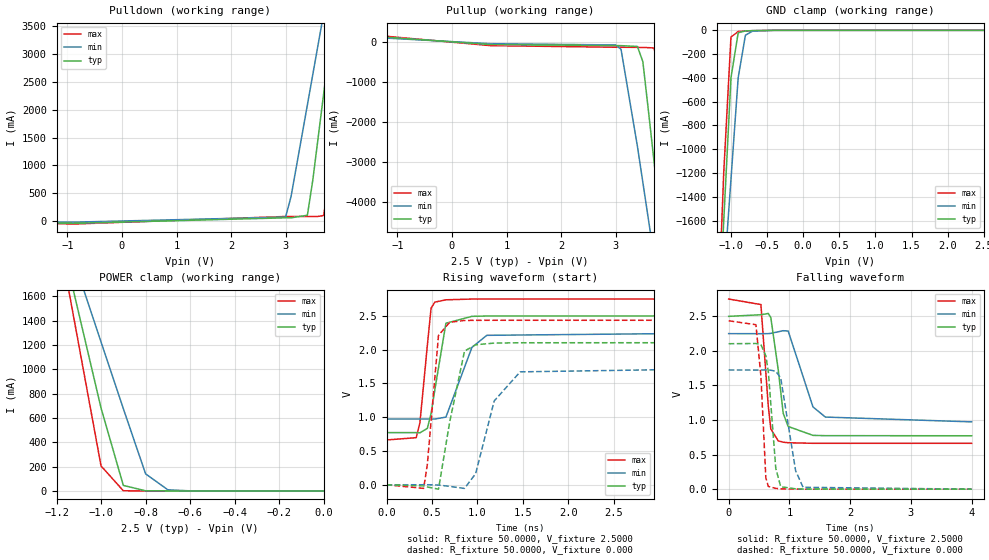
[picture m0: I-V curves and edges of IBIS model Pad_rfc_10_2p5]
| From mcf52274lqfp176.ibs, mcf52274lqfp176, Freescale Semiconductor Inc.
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|   Model Pad_rfc_10_2p5
[Model]   Pad_rfc_10_2p5
Model_type   3-state
Polarity   Non-Inverting
Enable   Active-High
Vmeas =   1.2500V
C_comp   1.7450pF   1.6200pF   1.8900pF
[Temperature Range]   25.0000   0.1500k   -40.0000
[Voltage Range]   2.5000V   2.2500V   2.7500V
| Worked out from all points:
|   slope of the pulldown table from 0 to 0.375 V, typ, clamps not added: 19.7 ohm
|   slope of the pullup table from 0 to 0.375 V, typ, clamps not added: 9.34 ohm
|   GND clamp passes 1 mA (typ) near -0.62 V on its own axis
|   POWER clamp passes 1 mA (typ) near -0.80 V on its own axis
|   rising waveform, R_fixture 50.0000, V_fixture 2.5000: 20-80 % time 119ps typ, 169ps min, 88.2ps max; typ from 0.772 V to 2.5 V
|   rising waveform, R_fixture 50.0000, V_fixture 0.000: 20-80 % time 141ps typ, 226ps min, 92.3ps max; typ from 0 V to 2.1 V
|   falling waveform, R_fixture 50.0000, V_fixture 2.5000: 20-80 % time 134ps typ, 249ps min, 97.3ps max; typ from 2.5 V to 0.772 V
|   falling waveform, R_fixture 50.0000, V_fixture 0.000: 20-80 % time 109ps typ, 183ps min, 83.4ps max; typ from 2.1 V to 0 V
[Pulldown]
| voltage   I(typ)   I(min)   I(max)
-2.5V     -1.24mA    -830uA     -1.5mA
-900mV    -41mA      -20.4mA    -54.37mA
3V        57.72mA    70.72mA    81.74mA
3.1V      57.87mA    437.7mA    81.94mA
3.4V      103.7mA    2.085A     82.48mA
3.5V      739.4mA    2.636A     82.66mA
3.6V      1.518A     3.187A     82.95mA
3.7V      2.298A     3.738A     100.1mA
3.8V      3.078A     4.29A      786mA
4V        4.642A     5.395A     2.779A
4.2V      6.207A     6.501A     4.776A
5V        12.49A     10.94A     12.79A
[Pullup]
| voltage   I(typ)   I(min)   I(max)
-2.5V     244.7mA    192.1mA    303.3mA
700mV     -63.31mA   -41.48mA   -90.21mA
3V        -89.95mA   -73.71mA   -130.9mA
3.1V      -90.83mA   -180.6mA   -131.3mA
3.4V      -111.1mA   -2.604A    -133.9mA
3.5V      -490mA     -3.509A    -136.8mA
3.6V      -1.692A    -4.417A    -140.7mA
3.7V      -2.924A    -5.323A    -149.7mA
3.8V      -4.171A    -6.231A    -564mA
4V        -6.686A    -8.057A    -3.659A
4.2V      -9.216A    -9.892A    -6.778A
5V        -19.38A    -17.29A    -19.43A
[GND_clamp]
| voltage   I(typ)   I(min)   I(max)
-2.5V     -19.27A    -14.9A     -23.25A
-1.2V     -2.833A    -2.997A    -2.746A
-1.1V     -1.601A    -2.108A    -1.195A
-1V       -399mA     -1.252A    -56.61mA
-900mV    -20.31mA   -398.2mA   -10.19mA
-800mV    -5.193mA   -41.09mA   -5.939mA
-700mV    -2.389mA   -6.145mA   -2.797mA
-400mV    -10.19uA   -60.07uA   -3.537uA
2.5V      1.128nA    208.6nA    39.38pA
[POWER_clamp]
| voltage   I(typ)   I(min)   I(max)
-2.5V     12.42A     9.511A     15.21A
-1.2V     2.239A     2.325A     2.196A
-1.1V     1.46A      1.775A     1.201A
-1V       681mA      1.225A     205.3mA
-900mV    45.39mA    676.7mA    1.42mA
-800mV    926.4uA    140.3mA    9.917uA
-700mV    19.11uA    9.036mA    78.78nA
-600mV    428.3nA    583.1uA    762.2pA
0V        1.128nA    78.54nA    61.1pA
[Ramp]
| variable   typ   min   max
dV/dt_r   1.2623/0.1214n   1.0341/0.2216n   1.4616/78.6184p
dV/dt_f   1.0365/0.1386n   0.7658/0.2455n   1.2520/89.8482p
R_load = 50.0000
[Rising Waveform]
R_fixture = 50.0000
V_fixture = 2.5000
V_fixture_min = 2.2500
V_fixture_max = 2.7500
| time   V(typ)   V(min)   V(max)
0s        772.5mV    973.6mV    663.4mV
326.5ps   772.4mV    973.5mV    697.5mV
367.3ps   769.4mV    973.7mV    919.1mV
449ps     836mV      974.2mV    2.067V
489.8ps   1.055V     974.1mV    2.615V
530.6ps   1.401V     973.1mV    2.704V
653.1ps   2.392V     1.002V     2.739V
938.8ps   2.494V     2.034V     2.75V
1.102ns   2.499V     2.213V     2.75V
4ns       2.5V       2.25V      2.75V
[Rising Waveform]
R_fixture = 50.0000
V_fixture = 0.000
| time   V(typ)   V(min)   V(max)
0s        269pV      1.393nV    136pV
408.2ps   -17.43mV   341.6uV    -53.62mV
449ps     -32.91mV   609.1uV    304.8mV
571.4ps   -65.12mV   -4.228mV   2.212V
693.9ps   925.6mV    -23.67mV   2.406V
857.1ps   1.979V     -54.34mV   2.433V
979.6ps   2.073V     163.8mV    2.435V
1.184ns   2.098V     1.242V     2.436V
1.469ns   2.103V     1.672V     2.436V
4ns       2.104V     1.724V     2.436V
[Falling Waveform]
R_fixture = 50.0000
V_fixture = 2.5000
V_fixture_min = 2.2500
V_fixture_max = 2.7500
| time   V(typ)   V(min)   V(max)
0s        2.5V       2.25V      2.75V
530.6ps   2.523V     2.249V     2.671V
653.1ps   2.542V     2.25V      1.191V
693.9ps   2.482V     2.254V     870.6mV
816.3ps   1.726V     2.277V     698.9mV
898ps     1.097V     2.292V     679.8mV
979.6ps   906.9mV    2.288V     671.6mV
1.388ns   778.2mV    1.19V      663.5mV
1.592ns   774mV      1.043V     663.4mV
4ns       772.5mV    973.6mV    663.4mV
[Falling Waveform]
R_fixture = 50.0000
V_fixture = 0.000
| time   V(typ)   V(min)   V(max)
0s        2.104V     1.724V     2.436V
449ps     2.107V     1.723V     2.379V
530.6ps   2.093V     1.723V     1.638V
612.2ps   1.927V     1.725V     163.7mV
653.1ps   1.698V     1.728V     39.18mV
775.5ps   302.6mV    1.706V     11.23mV
857.1ps   34.51mV    1.608V     4.918mV
1.102ns   5.047mV    267.6mV    541.5uV
1.225ns   1.995mV    27.04mV    143.4uV
4ns       1.554uV    -5.443uV   1.441uV
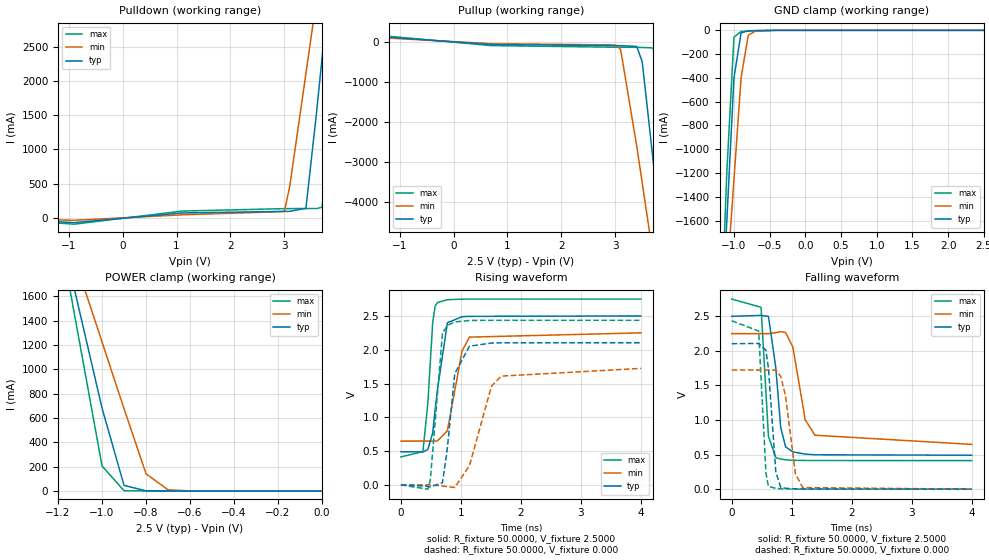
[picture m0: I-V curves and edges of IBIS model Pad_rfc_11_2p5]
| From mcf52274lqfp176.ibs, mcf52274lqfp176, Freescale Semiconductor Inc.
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|   Model Pad_rfc_11_2p5
[Model]   Pad_rfc_11_2p5
Model_type   3-state
Polarity   Non-Inverting
Enable   Active-High
Vmeas =   1.2500V
C_comp   1.7450pF   1.6200pF   1.8900pF
[Temperature Range]   25.0000   0.1500k   -40.0000
[Voltage Range]   2.5000V   2.2500V   2.7500V
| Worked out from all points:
|   slope of the pulldown table from 0 to 0.375 V, typ, clamps not added: 11.8 ohm
|   slope of the pullup table from 0 to 0.375 V, typ, clamps not added: 9.34 ohm
|   GND clamp passes 1 mA (typ) near -0.62 V on its own axis
|   POWER clamp passes 1 mA (typ) near -0.80 V on its own axis
|   rising waveform, R_fixture 50.0000, V_fixture 2.5000: 20-80 % time 167ps typ, 185ps min, 103ps max; typ from 0.491 V to 2.5 V
|   rising waveform, R_fixture 50.0000, V_fixture 0.000: 20-80 % time 148ps typ, 321ps min, 127ps max; typ from 0 V to 2.1 V
|   falling waveform, R_fixture 50.0000, V_fixture 2.5000: 20-80 % time 116ps typ, 191ps min, 87.1ps max; typ from 2.5 V to 0.491 V
|   falling waveform, R_fixture 50.0000, V_fixture 0.000: 20-80 % time 103ps typ, 146ps min, 80.2ps max; typ from 2.1 V to 0 V
[Pulldown]
| voltage   I(typ)   I(min)   I(max)
-2.5V     -2.06mA    -1.38mA    -2.51mA
-900mV    -68.33mA   -34mA      -90.62mA
1.1V      73.06mA    45.7mA     100.5mA
3V        96.19mA    94.13mA    136.2mA
3.1V      96.45mA    461.1mA    136.6mA
3.4V      142.5mA    2.109A     137.5mA
3.6V      1.557A     3.211A     138.2mA
3.7V      2.337A     3.762A     155.4mA
3.8V      3.118A     4.314A     841.5mA
4V        4.681A     5.419A     2.834A
4.2V      6.247A     6.526A     4.832A
5V        12.53A     10.96A     12.85A
[Pullup]
| voltage   I(typ)   I(min)   I(max)
-2.5V     244.7mA    192.1mA    303.3mA
700mV     -63.31mA   -41.48mA   -90.21mA
3V        -89.95mA   -73.71mA   -130.9mA
3.1V      -90.83mA   -180.6mA   -131.3mA
3.4V      -111.1mA   -2.604A    -133.9mA
3.5V      -490mA     -3.509A    -136.8mA
3.6V      -1.692A    -4.417A    -140.7mA
3.7V      -2.924A    -5.323A    -149.7mA
3.8V      -4.171A    -6.231A    -564mA
4V        -6.686A    -8.057A    -3.659A
4.2V      -9.216A    -9.892A    -6.778A
5V        -19.38A    -17.29A    -19.43A
[GND_clamp]
| voltage   I(typ)   I(min)   I(max)
-2.5V     -19.27A    -14.9A     -23.25A
-1.2V     -2.833A    -2.997A    -2.746A
-1.1V     -1.601A    -2.108A    -1.195A
-1V       -399mA     -1.252A    -56.61mA
-900mV    -20.31mA   -398.2mA   -10.19mA
-800mV    -5.193mA   -41.09mA   -5.939mA
-700mV    -2.389mA   -6.145mA   -2.797mA
-400mV    -10.19uA   -60.07uA   -3.537uA
2.5V      1.128nA    208.6nA    39.38pA
[POWER_clamp]
| voltage   I(typ)   I(min)   I(max)
-2.5V     12.42A     9.511A     15.21A
-1.2V     2.239A     2.325A     2.196A
-1.1V     1.46A      1.775A     1.201A
-1V       681mA      1.225A     205.3mA
-900mV    45.39mA    676.7mA    1.42mA
-800mV    926.4uA    140.3mA    9.917uA
-700mV    19.11uA    9.036mA    78.78nA
-600mV    428.3nA    583.1uA    762.2pA
0V        1.128nA    78.54nA    61.1pA
[Ramp]
| variable   typ   min   max
dV/dt_r   1.2623/0.1684n   1.0341/0.3167n   1.4616/0.1076n
dV/dt_f   1.2054/0.1112n   0.9614/0.2008n   1.4018/74.1078p
R_load = 50.0000
[Rising Waveform]
R_fixture = 50.0000
V_fixture = 2.5000
V_fixture_min = 2.2500
V_fixture_max = 2.7500
| time   V(typ)   V(min)   V(max)
0s        490.9mV    647.7mV    413.7mV
367.3ps   489.1mV    647.8mV    492.5mV
449ps     521.4mV    648.1mV    1.203V
530.6ps   769.2mV    646.7mV    2.404V
571.4ps   1.117V     647.6mV    2.648V
612.2ps   1.425V     652.5mV    2.699V
775.5ps   2.399V     803.1mV    2.74V
1.02ns    2.489V     1.982V     2.749V
1.143ns   2.494V     2.187V     2.75V
4ns       2.5V       2.25V      2.75V
[Rising Waveform]
R_fixture = 50.0000
V_fixture = 0.000
| time   V(typ)   V(min)   V(max)
0s        242.4pV    1.085nV    110pV
449ps     -20.18mV   579.7uV    -63.05mV
489.8ps   -28.8mV    561.5uV    67.64mV
693.9ps   32.15mV    -15.67mV   2.248V
775.5ps   550.5mV    -25.84mV   2.36V
898ps     1.647V     -37.71mV   2.412V
1.143ns   2.053V     284.3mV    2.433V
1.51ns    2.099V     1.462V     2.436V
1.674ns   2.102V     1.61V      2.436V
4ns       2.104V     1.724V     2.436V
[Falling Waveform]
R_fixture = 50.0000
V_fixture = 2.5000
V_fixture_min = 2.2500
V_fixture_max = 2.7500
| time   V(typ)   V(min)   V(max)
0s        2.5V       2.25V      2.75V
489.8ps   2.514V     2.25V      2.631V
612.2ps   2.5V       2.249V     765.7mV
734.7ps   1.757V     2.263V     455.7mV
816.3ps   895.3mV    2.278V     436mV
898ps     611.8mV    2.267V     425mV
1.02ns    539.3mV    2.053V     418.9mV
1.225ns   507.5mV    1.003V     415.1mV
1.388ns   497.3mV    780.3mV    414.2mV
4ns       490.9mV    647.7mV    413.7mV
[Falling Waveform]
R_fixture = 50.0000
V_fixture = 0.000
| time   V(typ)   V(min)   V(max)
0s        2.104V     1.724V     2.436V
449ps     2.108V     1.723V     2.288V
571.4ps   2.008V     1.724V     224.3mV
612.2ps   1.75V      1.724V     39.77mV
734.7ps   251.6mV    1.722V     11.9mV
816.3ps   27.71mV    1.634V     4.703mV
898ps     12.9mV     1.347V     2.331mV
1.061ns   4.459mV    224.9mV    728.3uV
1.184ns   2.364mV    22.74mV    275.3uV
4ns       1.076uV    19.62uV    942.5nV
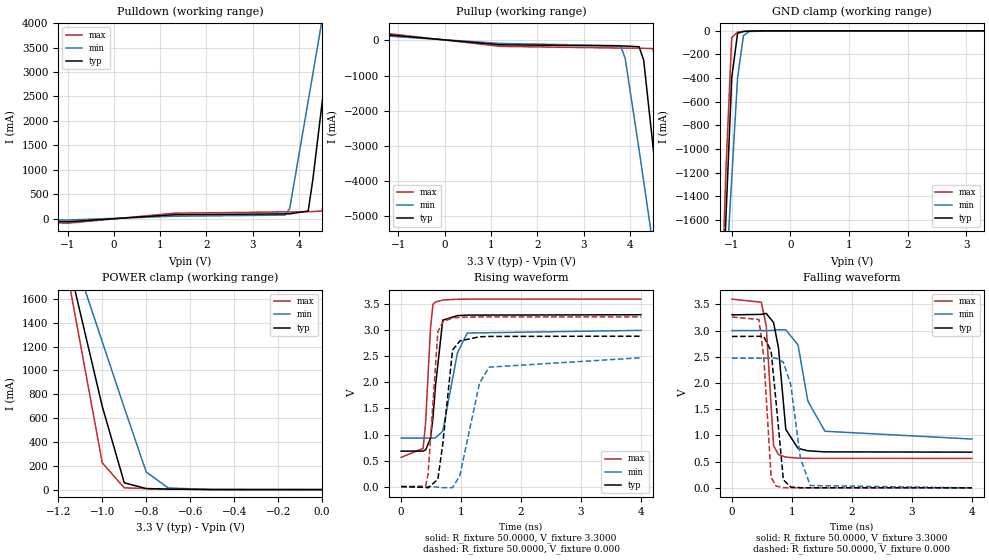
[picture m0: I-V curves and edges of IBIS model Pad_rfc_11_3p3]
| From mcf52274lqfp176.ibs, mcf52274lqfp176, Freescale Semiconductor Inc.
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|   Model Pad_rfc_11_3p3
[Model]   Pad_rfc_11_3p3
Model_type   3-state
Polarity   Non-Inverting
Enable   Active-High
Vmeas =   1.6500V
C_comp   1.7450pF   1.6200pF   1.8900pF
[Temperature Range]   25.0000   0.1500k   -40.0000
[Voltage Range]   3.3000V   3.0000V   3.6000V
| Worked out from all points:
|   slope of the pulldown table from 0 to 0.495 V, typ, clamps not added: 12.2 ohm
|   slope of the pullup table from 0 to 0.495 V, typ, clamps not added: 7.35 ohm
|   GND clamp passes 1 mA (typ) near -0.62 V on its own axis
|   POWER clamp passes 1 mA (typ) near -0.55 V on its own axis
|   rising waveform, R_fixture 50.0000, V_fixture 3.3000: 20-80 % time 120ps typ, 184ps min, 84.7ps max; typ from 0.681 V to 3.3 V
|   rising waveform, R_fixture 50.0000, V_fixture 0.000: 20-80 % time 144ps typ, 247ps min, 112ps max; typ from 0 V to 2.89 V
|   falling waveform, R_fixture 50.0000, V_fixture 3.3000: 20-80 % time 127ps typ, 238ps min, 90.1ps max; typ from 3.3 V to 0.681 V
|   falling waveform, R_fixture 50.0000, V_fixture 0.000: 20-80 % time 114ps typ, 177ps min, 92.5ps max; typ from 2.89 V to 0 V
[Pulldown]
| voltage   I(typ)   I(min)   I(max)
-3.3V     -960uA     -690uA     -1.12mA
-1V       -64.42mA   -28.73mA   -93.59mA
1.3V      80.13mA    49.72mA    111mA
3.7V      97.89mA    73.22mA    138.3mA
3.8V      98.46mA    207.5mA    138.7mA
4.2V      156.2mA    2.406A     141.8mA
4.3V      796.7mA    2.959A     145.2mA
4.5V      2.365A     4.067A     156.4mA
4.7V      3.935A     5.176A     1.369A
4.9V      5.507A     6.286A     3.375A
5.1V      7.08A      7.397A     5.384A
6.6V      18.91A     15.75A     20.49A
[Pullup]
| voltage   I(typ)   I(min)   I(max)
-3.3V     244.9mA    215.1mA    284.9mA
-1.5V     192.1mA    148mA      237.4mA
1.2V      -124.2mA   -85.59mA   -168.9mA
3.8V      -157.7mA   -149mA     -218.2mA
3.9V      -158.8mA   -506.4mA   -218.8mA
4.2V      -179.6mA   -3.106A    -221.2mA
4.3V      -558.8mA   -4.013A    -223.9mA
4.5V      -2.994A    -5.827A    -232.9mA
4.7V      -5.497A    -7.651A    -1.42A
4.9V      -8.023A    -9.485A    -4.532A
5.1V      -10.56A    -11.33A    -7.657A
6.6V      -29.85A    -25.37A    -31.75A
[GND_clamp]
| voltage   I(typ)   I(min)   I(max)
-3.3V     -29.47A    -22.32A    -36.02A
-1.2V     -2.833A    -2.997A    -2.746A
-1.1V     -1.601A    -2.108A    -1.195A
-1V       -399mA     -1.252A    -56.61mA
-900mV    -20.31mA   -398.2mA   -10.19mA
-800mV    -5.193mA   -41.09mA   -5.939mA
-700mV    -2.389mA   -6.145mA   -2.797mA
-400mV    -10.19uA   -60.09uA   -3.537uA
3.3V      1.753nA    18.97uA    123.1pA
[POWER_clamp]
| voltage   I(typ)   I(min)   I(max)
-3.3V     18.78A     14A        23.32A
-1.2V     2.265A     2.345A     2.228A
-1.1V     1.481A     1.792A     1.226A
-1V       697mA      1.24A      224.1mA
-900mV    56.88mA    687.4mA    14.75mA
-800mV    8.425mA    147.7mA    8.532mA
-700mV    4.193mA    13.57mA    4.564mA
-500mV    349.8uA    802.1uA    248.4uA
0V        1.753nA    96.55nA    128.5pA
[Ramp]
| variable   typ   min   max
dV/dt_r   1.7328/0.1503n   1.4845/0.2742n   1.9554/0.1002n
dV/dt_f   1.5712/0.1272n   1.2412/0.2223n   1.8228/88.2325p
R_load = 50.0000
[Rising Waveform]
R_fixture = 50.0000
V_fixture = 3.3000
V_fixture_min = 3.0000
V_fixture_max = 3.6000
| time   V(typ)   V(min)   V(max)
0s        681.3mV    931.2mV    562.1mV
367.3ps   683mV      931.4mV    734.5mV
408.2ps   705.4mV    931.6mV    1.233V
489.8ps   925.4mV    930.8mV    3.044V
530.6ps   1.32V      930.1mV    3.501V
571.4ps   1.917V     934.9mV    3.543V
693.9ps   3.196V     1.065V     3.583V
938.8ps   3.283V     2.567V     3.597V
1.102ns   3.293V     2.949V     3.599V
4ns       3.3V       3V         3.6V
[Rising Waveform]
R_fixture = 50.0000
V_fixture = 0.000
| time   V(typ)   V(min)   V(max)
0s        737.3pV    152.1nV    -241.6pV
408.2ps   -15.68mV   336.4uV    8.068mV
449ps     -23.97mV   628.9uV    234.1mV
612.2ps   138.8mV    -9.505mV   2.974V
693.9ps   814.6mV    -20.99mV   3.162V
857.1ps   2.62V      -20.7mV    3.239V
979.6ps   2.797V     213.8mV    3.251V
1.306ns   2.877V     1.983V     3.259V
1.469ns   2.884V     2.294V     3.259V
4ns       2.888V     2.474V     3.259V
[Falling Waveform]
R_fixture = 50.0000
V_fixture = 3.3000
V_fixture_min = 3.0000
V_fixture_max = 3.6000
| time   V(typ)   V(min)   V(max)
0s        3.3V       3V         3.6V
489.8ps   3.309V     3V         3.541V
571.4ps   3.327V     2.999V     3.087V
693.9ps   3.154V     3.005V     807.4mV
775.5ps   2.671V     3.016V     634.5mV
898ps     1.114V     3.014V     586.4mV
1.102ns   753.1mV    2.727V     566.5mV
1.265ns   706.7mV    1.657V     563.9mV
1.551ns   686.5mV    1.08V      562.5mV
4ns       681.3mV    931.3mV    562.1mV
[Falling Waveform]
R_fixture = 50.0000
V_fixture = 0.000
| time   V(typ)   V(min)   V(max)
0s        2.888V     2.474V     3.259V
449ps     2.891V     2.474V     3.212V
530.6ps   2.886V     2.474V     2.494V
653.1ps   2.607V     2.476V     203.5mV
734.7ps   1.646V     2.474V     33.81mV
857.1ps   153.1mV    2.396V     4.312mV
979.6ps   14.95mV    1.97V      1.569mV
1.143ns   3.331mV    558mV      266.3uV
1.306ns   1.254mV    43.56mV    215.6uV
4ns       1.473uV    35.83uV    1.25uV
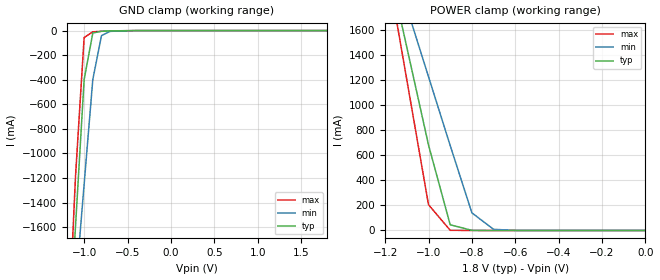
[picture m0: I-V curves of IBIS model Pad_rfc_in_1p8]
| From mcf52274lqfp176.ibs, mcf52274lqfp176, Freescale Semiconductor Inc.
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|   Model Pad_rfc_in_1p8
[Model]   Pad_rfc_in_1p8
Model_type   Input
Polarity   Non-Inverting
Vinl =   0.5400V
Vinh =   1.2600V
C_comp   1.7450pF   1.6200pF   1.8900pF
[Temperature Range]   25.0000   0.1500k   -40.0000
[Voltage Range]   1.8000V   1.6200V   1.9800V
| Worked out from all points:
|   GND clamp passes 1 mA (typ) near -0.62 V on its own axis
|   POWER clamp passes 1 mA (typ) near -0.80 V on its own axis
[GND_clamp]
| voltage   I(typ)   I(min)   I(max)
-1.8V     -10.39A    -8.454A    -12.14A
-1.2V     -2.833A    -2.997A    -2.746A
-1.1V     -1.601A    -2.108A    -1.195A
-1V       -399mA     -1.252A    -56.61mA
-900mV    -20.31mA   -398.2mA   -10.19mA
-800mV    -5.193mA   -41.09mA   -5.939mA
-700mV    -2.389mA   -6.145mA   -2.797mA
-400mV    -10.19uA   -60.07uA   -3.537uA
1.8V      460.9pA    80.51nA    11.42pA
[POWER_clamp]
| voltage   I(typ)   I(min)   I(max)
-1.8V     6.91A      5.617A     8.169A
-1.2V     2.238A     2.322A     2.196A
-1.1V     1.459A     1.774A     1.2A
-1V       681mA      1.225A     205.3mA
-900mV    45.38mA    676.7mA    1.42mA
-800mV    926.3uA    140.3mA    9.915uA
-700mV    19.1uA     9.035mA    78.66nA
-600mV    427.3nA    583uA      682.7pA
0V        460.9pA    46.96nA    15.9pA
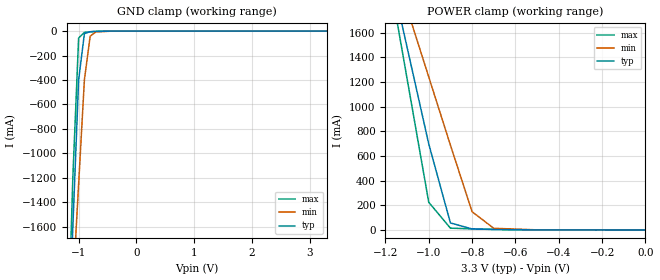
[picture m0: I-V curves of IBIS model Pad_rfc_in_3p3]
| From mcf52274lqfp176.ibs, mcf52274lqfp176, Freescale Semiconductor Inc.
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|   Model Pad_rfc_in_3p3
[Model]   Pad_rfc_in_3p3
Model_type   Input
Polarity   Non-Inverting
Vinl =   0.9900V
Vinh =   2.3100V
C_comp   1.7450pF   1.6200pF   1.8900pF
[Temperature Range]   25.0000   0.1500k   -40.0000
[Voltage Range]   3.3000V   3.0000V   3.6000V
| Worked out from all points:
|   GND clamp passes 1 mA (typ) near -0.62 V on its own axis
|   POWER clamp passes 1 mA (typ) near -0.55 V on its own axis
[GND_clamp]
| voltage   I(typ)   I(min)   I(max)
-3.3V     -29.47A    -22.32A    -36.02A
-1.2V     -2.833A    -2.997A    -2.746A
-1.1V     -1.601A    -2.108A    -1.195A
-1V       -399mA     -1.252A    -56.61mA
-900mV    -20.31mA   -398.2mA   -10.19mA
-800mV    -5.193mA   -41.09mA   -5.939mA
-700mV    -2.389mA   -6.145mA   -2.797mA
-400mV    -10.19uA   -60.09uA   -3.537uA
3.3V      1.753nA    18.97uA    123.1pA
[POWER_clamp]
| voltage   I(typ)   I(min)   I(max)
-3.3V     18.78A     14A        23.32A
-1.2V     2.265A     2.345A     2.228A
-1.1V     1.481A     1.792A     1.226A
-1V       697mA      1.24A      224.1mA
-900mV    56.88mA    687.4mA    14.75mA
-800mV    8.425mA    147.7mA    8.532mA
-700mV    4.193mA    13.57mA    4.564mA
-500mV    349.8uA    801.9uA    248.4uA
0V        1.753nA    96.56nA    128.5pA
